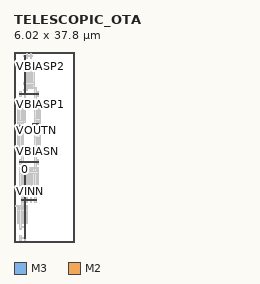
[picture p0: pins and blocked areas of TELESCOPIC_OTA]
MACRO TELESCOPIC_OTA
  ORIGIN 0 0 ;
  FOREIGN TELESCOPIC_OTA 0 0 ;
  SIZE 6.02 BY 37.8 ;
  PIN 0
    DIRECTION INOUT ;
    USE SIGNAL ;
    PORT 
      LAYER M3 ;
        RECT 2.01 0.68 2.29 6.46 ;
      LAYER M2 ;
        RECT 1.55 8.26 4.47 8.54 ;
      LAYER M2 ;
        RECT 1.12 15.82 4.9 16.1 ;
      LAYER M3 ;
        RECT 2.01 6.3 2.29 8.4 ;
      LAYER M2 ;
        RECT 1.99 8.26 2.31 8.54 ;
      LAYER M3 ;
        RECT 2.01 8.4 2.29 15.96 ;
      LAYER M2 ;
        RECT 1.99 15.82 2.31 16.1 ;
    END
  END 0
  PIN VBIASP2
    DIRECTION INOUT ;
    USE SIGNAL ;
    PORT 
      LAYER M2 ;
        RECT 2.41 34.72 3.61 35 ;
    END
  END VBIASP2
  PIN VDD
    DIRECTION INOUT ;
    USE SIGNAL ;
    PORT 
      LAYER M2 ;
        RECT 1.12 29.26 4.9 29.54 ;
      LAYER M3 ;
        RECT 2.01 31.34 2.29 37.12 ;
      LAYER M2 ;
        RECT 1.99 29.26 2.31 29.54 ;
      LAYER M3 ;
        RECT 2.01 29.4 2.29 31.5 ;
    END
  END VDD
  PIN VOUTN
    DIRECTION INOUT ;
    USE SIGNAL ;
    PORT 
      LAYER M2 ;
        RECT 1.12 22.12 2.32 22.4 ;
      LAYER M2 ;
        RECT 1.12 22.96 2.32 23.24 ;
      LAYER M2 ;
        RECT 1.56 22.12 1.88 22.4 ;
      LAYER M3 ;
        RECT 1.58 22.26 1.86 23.1 ;
      LAYER M2 ;
        RECT 1.56 22.96 1.88 23.24 ;
    END
  END VOUTN
  PIN VOUTP
    DIRECTION INOUT ;
    USE SIGNAL ;
    PORT 
      LAYER M2 ;
        RECT 3.7 21.7 4.9 21.98 ;
      LAYER M2 ;
        RECT 3.7 23.38 4.9 23.66 ;
      LAYER M2 ;
        RECT 4.14 21.7 4.46 21.98 ;
      LAYER M3 ;
        RECT 4.16 21.84 4.44 23.52 ;
      LAYER M2 ;
        RECT 4.14 23.38 4.46 23.66 ;
    END
  END VOUTP
  PIN VBIASN
    DIRECTION INOUT ;
    USE SIGNAL ;
    PORT 
      LAYER M2 ;
        RECT 1.12 17.92 4.9 18.2 ;
    END
  END VBIASN
  PIN VBIASP1
    DIRECTION INOUT ;
    USE SIGNAL ;
    PORT 
      LAYER M2 ;
        RECT 1.12 27.16 4.9 27.44 ;
    END
  END VBIASP1
  PIN VINP
    DIRECTION INOUT ;
    USE SIGNAL ;
    PORT 
      LAYER M2 ;
        RECT 1.55 10.36 4.47 10.64 ;
    END
  END VINP
  PIN VINN
    DIRECTION INOUT ;
    USE SIGNAL ;
    PORT 
      LAYER M2 ;
        RECT 2.41 9.94 3.61 10.22 ;
    END
  END VINN
  OBS 
  LAYER M3 ;
        RECT 1.15 2.78 1.43 7.3 ;
  LAYER M2 ;
        RECT 1.12 6.58 2.32 6.86 ;
  LAYER M2 ;
        RECT 1.12 13.72 4.9 14 ;
  LAYER M2 ;
        RECT 1.56 6.58 1.88 6.86 ;
  LAYER M3 ;
        RECT 1.58 6.72 1.86 13.86 ;
  LAYER M2 ;
        RECT 1.56 13.72 1.88 14 ;
  LAYER M2 ;
        RECT 1.56 6.58 1.88 6.86 ;
  LAYER M3 ;
        RECT 1.58 6.56 1.86 6.88 ;
  LAYER M2 ;
        RECT 1.56 13.72 1.88 14 ;
  LAYER M3 ;
        RECT 1.58 13.7 1.86 14.02 ;
  LAYER M2 ;
        RECT 1.56 6.58 1.88 6.86 ;
  LAYER M3 ;
        RECT 1.58 6.56 1.86 6.88 ;
  LAYER M2 ;
        RECT 1.56 13.72 1.88 14 ;
  LAYER M3 ;
        RECT 1.58 13.7 1.86 14.02 ;
  LAYER M2 ;
        RECT 4.13 24.22 5.33 24.5 ;
  LAYER M2 ;
        RECT 3.27 30.52 4.47 30.8 ;
  LAYER M2 ;
        RECT 4.14 24.22 4.46 24.5 ;
  LAYER M3 ;
        RECT 4.16 24.36 4.44 30.66 ;
  LAYER M2 ;
        RECT 4.14 30.52 4.46 30.8 ;
  LAYER M2 ;
        RECT 4.14 24.22 4.46 24.5 ;
  LAYER M3 ;
        RECT 4.16 24.2 4.44 24.52 ;
  LAYER M2 ;
        RECT 4.14 30.52 4.46 30.8 ;
  LAYER M3 ;
        RECT 4.16 30.5 4.44 30.82 ;
  LAYER M2 ;
        RECT 4.14 24.22 4.46 24.5 ;
  LAYER M3 ;
        RECT 4.16 24.2 4.44 24.52 ;
  LAYER M2 ;
        RECT 4.14 30.52 4.46 30.8 ;
  LAYER M3 ;
        RECT 4.16 30.5 4.44 30.82 ;
  LAYER M2 ;
        RECT 0.69 23.8 1.89 24.08 ;
  LAYER M2 ;
        RECT 2.41 30.94 3.61 31.22 ;
  LAYER M2 ;
        RECT 1.72 23.8 2.15 24.08 ;
  LAYER M1 ;
        RECT 2.025 23.94 2.275 30.24 ;
  LAYER M2 ;
        RECT 2.15 30.1 2.58 30.38 ;
  LAYER M3 ;
        RECT 2.44 30.24 2.72 31.08 ;
  LAYER M2 ;
        RECT 2.42 30.94 2.74 31.22 ;
  LAYER M1 ;
        RECT 2.025 23.855 2.275 24.025 ;
  LAYER M2 ;
        RECT 1.98 23.8 2.32 24.08 ;
  LAYER M1 ;
        RECT 2.025 30.155 2.275 30.325 ;
  LAYER M2 ;
        RECT 1.98 30.1 2.32 30.38 ;
  LAYER M2 ;
        RECT 2.42 30.1 2.74 30.38 ;
  LAYER M3 ;
        RECT 2.44 30.08 2.72 30.4 ;
  LAYER M2 ;
        RECT 2.42 30.94 2.74 31.22 ;
  LAYER M3 ;
        RECT 2.44 30.92 2.72 31.24 ;
  LAYER M1 ;
        RECT 2.025 23.855 2.275 24.025 ;
  LAYER M2 ;
        RECT 1.98 23.8 2.32 24.08 ;
  LAYER M1 ;
        RECT 2.025 30.155 2.275 30.325 ;
  LAYER M2 ;
        RECT 1.98 30.1 2.32 30.38 ;
  LAYER M2 ;
        RECT 2.42 30.1 2.74 30.38 ;
  LAYER M3 ;
        RECT 2.44 30.08 2.72 30.4 ;
  LAYER M2 ;
        RECT 2.42 30.94 2.74 31.22 ;
  LAYER M3 ;
        RECT 2.44 30.92 2.72 31.24 ;
  LAYER M2 ;
        RECT 1.55 14.56 4.47 14.84 ;
  LAYER M2 ;
        RECT 0.69 21.28 1.89 21.56 ;
  LAYER M2 ;
        RECT 1.56 14.56 1.88 14.84 ;
  LAYER M3 ;
        RECT 1.58 14.7 1.86 21.42 ;
  LAYER M2 ;
        RECT 1.56 21.28 1.88 21.56 ;
  LAYER M2 ;
        RECT 1.56 14.56 1.88 14.84 ;
  LAYER M3 ;
        RECT 1.58 14.54 1.86 14.86 ;
  LAYER M2 ;
        RECT 1.56 21.28 1.88 21.56 ;
  LAYER M3 ;
        RECT 1.58 21.26 1.86 21.58 ;
  LAYER M2 ;
        RECT 1.56 14.56 1.88 14.84 ;
  LAYER M3 ;
        RECT 1.58 14.54 1.86 14.86 ;
  LAYER M2 ;
        RECT 1.56 21.28 1.88 21.56 ;
  LAYER M3 ;
        RECT 1.58 21.26 1.86 21.58 ;
  LAYER M2 ;
        RECT 2.41 14.14 3.61 14.42 ;
  LAYER M2 ;
        RECT 4.13 20.86 5.33 21.14 ;
  LAYER M2 ;
        RECT 3.44 14.14 4.3 14.42 ;
  LAYER M3 ;
        RECT 4.16 14.28 4.44 21 ;
  LAYER M2 ;
        RECT 4.14 20.86 4.46 21.14 ;
  LAYER M2 ;
        RECT 4.14 14.14 4.46 14.42 ;
  LAYER M3 ;
        RECT 4.16 14.12 4.44 14.44 ;
  LAYER M2 ;
        RECT 4.14 20.86 4.46 21.14 ;
  LAYER M3 ;
        RECT 4.16 20.84 4.44 21.16 ;
  LAYER M2 ;
        RECT 4.14 14.14 4.46 14.42 ;
  LAYER M3 ;
        RECT 4.16 14.12 4.44 14.44 ;
  LAYER M2 ;
        RECT 4.14 20.86 4.46 21.14 ;
  LAYER M3 ;
        RECT 4.16 20.84 4.44 21.16 ;
  LAYER M1 ;
        RECT 1.165 3.695 1.415 7.225 ;
  LAYER M1 ;
        RECT 1.165 2.435 1.415 3.445 ;
  LAYER M1 ;
        RECT 1.165 0.335 1.415 1.345 ;
  LAYER M1 ;
        RECT 0.735 3.695 0.985 7.225 ;
  LAYER M1 ;
        RECT 1.595 3.695 1.845 7.225 ;
  LAYER M1 ;
        RECT 2.025 3.695 2.275 7.225 ;
  LAYER M1 ;
        RECT 2.025 2.435 2.275 3.445 ;
  LAYER M1 ;
        RECT 2.025 0.335 2.275 1.345 ;
  LAYER M1 ;
        RECT 2.455 3.695 2.705 7.225 ;
  LAYER M2 ;
        RECT 1.12 2.8 2.32 3.08 ;
  LAYER M2 ;
        RECT 0.26 7 1.46 7.28 ;
  LAYER M2 ;
        RECT 0.69 6.16 2.75 6.44 ;
  LAYER M2 ;
        RECT 1.12 0.7 2.32 0.98 ;
  LAYER M3 ;
        RECT 1.15 2.78 1.43 7.3 ;
  LAYER M2 ;
        RECT 1.12 6.58 2.32 6.86 ;
  LAYER M3 ;
        RECT 2.01 0.68 2.29 6.46 ;
  LAYER M1 ;
        RECT 3.315 30.575 3.565 34.105 ;
  LAYER M1 ;
        RECT 3.315 34.355 3.565 35.365 ;
  LAYER M1 ;
        RECT 3.315 36.455 3.565 37.465 ;
  LAYER M1 ;
        RECT 3.745 30.575 3.995 34.105 ;
  LAYER M1 ;
        RECT 2.885 30.575 3.135 34.105 ;
  LAYER M1 ;
        RECT 2.455 30.575 2.705 34.105 ;
  LAYER M1 ;
        RECT 2.455 34.355 2.705 35.365 ;
  LAYER M1 ;
        RECT 2.455 36.455 2.705 37.465 ;
  LAYER M1 ;
        RECT 2.025 30.575 2.275 34.105 ;
  LAYER M2 ;
        RECT 1.98 31.36 4.04 31.64 ;
  LAYER M2 ;
        RECT 1.98 36.82 3.61 37.1 ;
  LAYER M2 ;
        RECT 3.27 30.52 4.47 30.8 ;
  LAYER M2 ;
        RECT 2.41 30.94 3.61 31.22 ;
  LAYER M2 ;
        RECT 2.41 34.72 3.61 35 ;
  LAYER M3 ;
        RECT 2.01 31.34 2.29 37.12 ;
  LAYER M1 ;
        RECT 1.165 18.815 1.415 22.345 ;
  LAYER M1 ;
        RECT 1.165 17.555 1.415 18.565 ;
  LAYER M1 ;
        RECT 1.165 15.455 1.415 16.465 ;
  LAYER M1 ;
        RECT 0.735 18.815 0.985 22.345 ;
  LAYER M1 ;
        RECT 1.595 18.815 1.845 22.345 ;
  LAYER M1 ;
        RECT 4.605 18.815 4.855 22.345 ;
  LAYER M1 ;
        RECT 4.605 17.555 4.855 18.565 ;
  LAYER M1 ;
        RECT 4.605 15.455 4.855 16.465 ;
  LAYER M1 ;
        RECT 4.175 18.815 4.425 22.345 ;
  LAYER M1 ;
        RECT 5.035 18.815 5.285 22.345 ;
  LAYER M2 ;
        RECT 1.12 15.82 4.9 16.1 ;
  LAYER M2 ;
        RECT 1.12 22.12 2.32 22.4 ;
  LAYER M2 ;
        RECT 3.7 21.7 4.9 21.98 ;
  LAYER M2 ;
        RECT 1.12 17.92 4.9 18.2 ;
  LAYER M2 ;
        RECT 0.69 21.28 1.89 21.56 ;
  LAYER M2 ;
        RECT 4.13 20.86 5.33 21.14 ;
  LAYER M1 ;
        RECT 1.165 23.015 1.415 26.545 ;
  LAYER M1 ;
        RECT 1.165 26.795 1.415 27.805 ;
  LAYER M1 ;
        RECT 1.165 28.895 1.415 29.905 ;
  LAYER M1 ;
        RECT 0.735 23.015 0.985 26.545 ;
  LAYER M1 ;
        RECT 1.595 23.015 1.845 26.545 ;
  LAYER M1 ;
        RECT 4.605 23.015 4.855 26.545 ;
  LAYER M1 ;
        RECT 4.605 26.795 4.855 27.805 ;
  LAYER M1 ;
        RECT 4.605 28.895 4.855 29.905 ;
  LAYER M1 ;
        RECT 4.175 23.015 4.425 26.545 ;
  LAYER M1 ;
        RECT 5.035 23.015 5.285 26.545 ;
  LAYER M2 ;
        RECT 1.12 29.26 4.9 29.54 ;
  LAYER M2 ;
        RECT 1.12 22.96 2.32 23.24 ;
  LAYER M2 ;
        RECT 3.7 23.38 4.9 23.66 ;
  LAYER M2 ;
        RECT 1.12 27.16 4.9 27.44 ;
  LAYER M2 ;
        RECT 0.69 23.8 1.89 24.08 ;
  LAYER M2 ;
        RECT 4.13 24.22 5.33 24.5 ;
  LAYER M1 ;
        RECT 1.595 11.255 1.845 14.785 ;
  LAYER M1 ;
        RECT 1.595 9.995 1.845 11.005 ;
  LAYER M1 ;
        RECT 1.595 7.895 1.845 8.905 ;
  LAYER M1 ;
        RECT 1.165 11.255 1.415 14.785 ;
  LAYER M1 ;
        RECT 2.025 11.255 2.275 14.785 ;
  LAYER M1 ;
        RECT 2.455 11.255 2.705 14.785 ;
  LAYER M1 ;
        RECT 2.455 9.995 2.705 11.005 ;
  LAYER M1 ;
        RECT 2.455 7.895 2.705 8.905 ;
  LAYER M1 ;
        RECT 2.885 11.255 3.135 14.785 ;
  LAYER M1 ;
        RECT 3.315 11.255 3.565 14.785 ;
  LAYER M1 ;
        RECT 3.315 9.995 3.565 11.005 ;
  LAYER M1 ;
        RECT 3.315 7.895 3.565 8.905 ;
  LAYER M1 ;
        RECT 3.745 11.255 3.995 14.785 ;
  LAYER M1 ;
        RECT 4.175 11.255 4.425 14.785 ;
  LAYER M1 ;
        RECT 4.175 9.995 4.425 11.005 ;
  LAYER M1 ;
        RECT 4.175 7.895 4.425 8.905 ;
  LAYER M1 ;
        RECT 4.605 11.255 4.855 14.785 ;
  LAYER M2 ;
        RECT 1.55 8.26 4.47 8.54 ;
  LAYER M2 ;
        RECT 1.55 14.56 4.47 14.84 ;
  LAYER M2 ;
        RECT 2.41 14.14 3.61 14.42 ;
  LAYER M2 ;
        RECT 1.55 10.36 4.47 10.64 ;
  LAYER M2 ;
        RECT 2.41 9.94 3.61 10.22 ;
  LAYER M2 ;
        RECT 1.12 13.72 4.9 14 ;
  END 
END TELESCOPIC_OTA
